VERSION 5.8 ;
NAMESCASESENSITIVE ON ;
BUSBITCHARS "[]" ;
DIVIDERCHAR "/" ;

UNITS
  DATABASE MICRONS 1000 ;
END UNITS

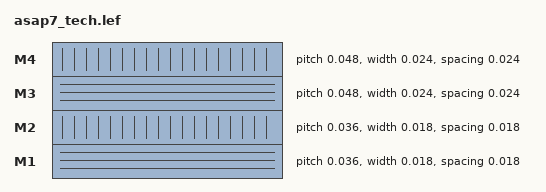
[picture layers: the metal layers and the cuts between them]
LAYER M1
  TYPE ROUTING ;
  DIRECTION HORIZONTAL ;
  PITCH 0.036 ;
  WIDTH 0.018 ;
  SPACING 0.018 ;
END M1

LAYER M2
  TYPE ROUTING ;
  DIRECTION VERTICAL ;
  PITCH 0.036 ;
  WIDTH 0.018 ;
  SPACING 0.018 ;
END M2

LAYER M3
  TYPE ROUTING ;
  DIRECTION HORIZONTAL ;
  PITCH 0.048 ;
  WIDTH 0.024 ;
  SPACING 0.024 ;
END M3

LAYER M4
  TYPE ROUTING ;
  DIRECTION VERTICAL ;
  PITCH 0.048 ;
  WIDTH 0.024 ;
  SPACING 0.024 ;
END M4
